VERSION 5.7 ;
  NOWIREEXTENSIONATPIN ON ;
  DIVIDERCHAR "/" ;
  BUSBITCHARS "[]" ;
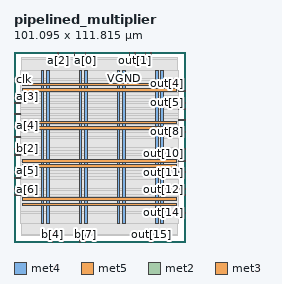
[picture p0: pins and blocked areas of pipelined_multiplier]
MACRO pipelined_multiplier
  CLASS BLOCK ;
  FOREIGN pipelined_multiplier ;
  ORIGIN 0.000 0.000 ;
  SIZE 101.095 BY 111.815 ;
  PIN VGND
    DIRECTION INOUT ;
    USE GROUND ;
    PORT
      LAYER met4 ;
        RECT 19.230 10.640 20.830 100.880 ;
    END
    PORT
      LAYER met4 ;
        RECT 41.655 10.640 43.255 100.880 ;
    END
    PORT
      LAYER met4 ;
        RECT 64.080 10.640 65.680 100.880 ;
    END
    PORT
      LAYER met4 ;
        RECT 86.505 10.640 88.105 100.880 ;
    END
    PORT
      LAYER met5 ;
        RECT 5.280 24.600 95.460 26.200 ;
    END
    PORT
      LAYER met5 ;
        RECT 5.280 47.040 95.460 48.640 ;
    END
    PORT
      LAYER met5 ;
        RECT 5.280 69.480 95.460 71.080 ;
    END
    PORT
      LAYER met5 ;
        RECT 5.280 91.920 95.460 93.520 ;
    END
  END VGND
  PIN VPWR
    DIRECTION INOUT ;
    USE POWER ;
    PORT
      LAYER met4 ;
        RECT 15.930 10.640 17.530 100.880 ;
    END
    PORT
      LAYER met4 ;
        RECT 38.355 10.640 39.955 100.880 ;
    END
    PORT
      LAYER met4 ;
        RECT 60.780 10.640 62.380 100.880 ;
    END
    PORT
      LAYER met4 ;
        RECT 83.205 10.640 84.805 100.880 ;
    END
    PORT
      LAYER met5 ;
        RECT 5.280 21.300 95.460 22.900 ;
    END
    PORT
      LAYER met5 ;
        RECT 5.280 43.740 95.460 45.340 ;
    END
    PORT
      LAYER met5 ;
        RECT 5.280 66.180 95.460 67.780 ;
    END
    PORT
      LAYER met5 ;
        RECT 5.280 88.620 95.460 90.220 ;
    END
  END VPWR
  PIN a[0]
    DIRECTION INPUT ;
    USE SIGNAL ;
    ANTENNAGATEAREA 0.196500 ;
    PORT
      LAYER met2 ;
        RECT 41.950 107.815 42.230 111.815 ;
    END
  END a[0]
  PIN a[1]
    DIRECTION INPUT ;
    USE SIGNAL ;
    ANTENNAGATEAREA 0.196500 ;
    PORT
      LAYER met2 ;
        RECT 35.510 107.815 35.790 111.815 ;
    END
  END a[1]
  PIN a[2]
    DIRECTION INPUT ;
    USE SIGNAL ;
    ANTENNAGATEAREA 0.196500 ;
    PORT
      LAYER met2 ;
        RECT 25.850 107.815 26.130 111.815 ;
    END
  END a[2]
  PIN a[3]
    DIRECTION INPUT ;
    USE SIGNAL ;
    ANTENNAGATEAREA 0.196500 ;
    PORT
      LAYER met3 ;
        RECT 0.000 85.040 4.000 85.640 ;
    END
  END a[3]
  PIN a[4]
    DIRECTION INPUT ;
    USE SIGNAL ;
    ANTENNAGATEAREA 0.196500 ;
    PORT
      LAYER met3 ;
        RECT 0.000 68.040 4.000 68.640 ;
    END
  END a[4]
  PIN a[5]
    DIRECTION INPUT ;
    USE SIGNAL ;
    ANTENNAGATEAREA 0.196500 ;
    PORT
      LAYER met3 ;
        RECT 0.000 37.440 4.000 38.040 ;
    END
  END a[5]
  PIN a[6]
    DIRECTION INPUT ;
    USE SIGNAL ;
    ANTENNAGATEAREA 0.196500 ;
    PORT
      LAYER met3 ;
        RECT 0.000 30.640 4.000 31.240 ;
    END
  END a[6]
  PIN a[7]
    DIRECTION INPUT ;
    USE SIGNAL ;
    ANTENNAGATEAREA 0.196500 ;
    PORT
      LAYER met3 ;
        RECT 0.000 27.240 4.000 27.840 ;
    END
  END a[7]
  PIN b[0]
    DIRECTION INPUT ;
    USE SIGNAL ;
    ANTENNAGATEAREA 0.196500 ;
    PORT
      LAYER met3 ;
        RECT 0.000 81.640 4.000 82.240 ;
    END
  END b[0]
  PIN b[1]
    DIRECTION INPUT ;
    USE SIGNAL ;
    ANTENNAGATEAREA 0.196500 ;
    PORT
      LAYER met3 ;
        RECT 0.000 74.840 4.000 75.440 ;
    END
  END b[1]
  PIN b[2]
    DIRECTION INPUT ;
    USE SIGNAL ;
    ANTENNAGATEAREA 0.196500 ;
    PORT
      LAYER met3 ;
        RECT 0.000 54.440 4.000 55.040 ;
    END
  END b[2]
  PIN b[3]
    DIRECTION INPUT ;
    USE SIGNAL ;
    ANTENNAGATEAREA 0.196500 ;
    PORT
      LAYER met3 ;
        RECT 0.000 61.240 4.000 61.840 ;
    END
  END b[3]
  PIN b[4]
    DIRECTION INPUT ;
    USE SIGNAL ;
    ANTENNAGATEAREA 0.196500 ;
    PORT
      LAYER met2 ;
        RECT 22.630 0.000 22.910 4.000 ;
    END
  END b[4]
  PIN b[5]
    DIRECTION INPUT ;
    USE SIGNAL ;
    ANTENNAGATEAREA 0.196500 ;
    PORT
      LAYER met2 ;
        RECT 29.070 0.000 29.350 4.000 ;
    END
  END b[5]
  PIN b[6]
    DIRECTION INPUT ;
    USE SIGNAL ;
    ANTENNAGATEAREA 0.196500 ;
    PORT
      LAYER met2 ;
        RECT 38.730 0.000 39.010 4.000 ;
    END
  END b[6]
  PIN b[7]
    DIRECTION INPUT ;
    USE SIGNAL ;
    ANTENNAGATEAREA 0.196500 ;
    PORT
      LAYER met2 ;
        RECT 41.950 0.000 42.230 4.000 ;
    END
  END b[7]
  PIN clk
    DIRECTION INPUT ;
    USE SIGNAL ;
    ANTENNAGATEAREA 0.742500 ;
    PORT
      LAYER met3 ;
        RECT 0.000 95.240 4.000 95.840 ;
    END
  END clk
  PIN out[0]
    DIRECTION OUTPUT TRISTATE ;
    USE SIGNAL ;
    ANTENNADIFFAREA 0.340600 ;
    PORT
      LAYER met2 ;
        RECT 67.710 107.815 67.990 111.815 ;
    END
  END out[0]
  PIN out[10]
    DIRECTION OUTPUT TRISTATE ;
    USE SIGNAL ;
    ANTENNADIFFAREA 0.340600 ;
    PORT
      LAYER met3 ;
        RECT 97.095 47.640 101.095 48.240 ;
    END
  END out[10]
  PIN out[11]
    DIRECTION OUTPUT TRISTATE ;
    USE SIGNAL ;
    ANTENNADIFFAREA 0.340600 ;
    PORT
      LAYER met3 ;
        RECT 97.095 40.840 101.095 41.440 ;
    END
  END out[11]
  PIN out[12]
    DIRECTION OUTPUT TRISTATE ;
    USE SIGNAL ;
    ANTENNADIFFAREA 0.340600 ;
    PORT
      LAYER met3 ;
        RECT 97.095 30.640 101.095 31.240 ;
    END
  END out[12]
  PIN out[13]
    DIRECTION OUTPUT TRISTATE ;
    USE SIGNAL ;
    ANTENNADIFFAREA 0.340600 ;
    PORT
      LAYER met3 ;
        RECT 97.095 27.240 101.095 27.840 ;
    END
  END out[13]
  PIN out[14]
    DIRECTION OUTPUT TRISTATE ;
    USE SIGNAL ;
    ANTENNADIFFAREA 0.340600 ;
    PORT
      LAYER met3 ;
        RECT 97.095 17.040 101.095 17.640 ;
    END
  END out[14]
  PIN out[15]
    DIRECTION OUTPUT TRISTATE ;
    USE SIGNAL ;
    ANTENNADIFFAREA 0.340600 ;
    PORT
      LAYER met2 ;
        RECT 80.590 0.000 80.870 4.000 ;
    END
  END out[15]
  PIN out[1]
    DIRECTION OUTPUT TRISTATE ;
    USE SIGNAL ;
    ANTENNADIFFAREA 0.340600 ;
    PORT
      LAYER met2 ;
        RECT 70.930 107.815 71.210 111.815 ;
    END
  END out[1]
  PIN out[2]
    DIRECTION OUTPUT TRISTATE ;
    USE SIGNAL ;
    ANTENNADIFFAREA 0.340600 ;
    PORT
      LAYER met2 ;
        RECT 77.370 107.815 77.650 111.815 ;
    END
  END out[2]
  PIN out[3]
    DIRECTION OUTPUT TRISTATE ;
    USE SIGNAL ;
    ANTENNADIFFAREA 0.340600 ;
    PORT
      LAYER met2 ;
        RECT 80.590 107.815 80.870 111.815 ;
    END
  END out[3]
  PIN out[4]
    DIRECTION OUTPUT TRISTATE ;
    USE SIGNAL ;
    ANTENNADIFFAREA 0.340600 ;
    PORT
      LAYER met3 ;
        RECT 97.095 88.440 101.095 89.040 ;
    END
  END out[4]
  PIN out[5]
    DIRECTION OUTPUT TRISTATE ;
    USE SIGNAL ;
    ANTENNADIFFAREA 0.340600 ;
    PORT
      LAYER met3 ;
        RECT 97.095 81.640 101.095 82.240 ;
    END
  END out[5]
  PIN out[6]
    DIRECTION OUTPUT TRISTATE ;
    USE SIGNAL ;
    ANTENNADIFFAREA 0.340600 ;
    PORT
      LAYER met3 ;
        RECT 97.095 78.240 101.095 78.840 ;
    END
  END out[6]
  PIN out[7]
    DIRECTION OUTPUT TRISTATE ;
    USE SIGNAL ;
    ANTENNADIFFAREA 0.340600 ;
    PORT
      LAYER met3 ;
        RECT 97.095 71.440 101.095 72.040 ;
    END
  END out[7]
  PIN out[8]
    DIRECTION OUTPUT TRISTATE ;
    USE SIGNAL ;
    ANTENNADIFFAREA 0.340600 ;
    PORT
      LAYER met3 ;
        RECT 97.095 64.640 101.095 65.240 ;
    END
  END out[8]
  PIN out[9]
    DIRECTION OUTPUT TRISTATE ;
    USE SIGNAL ;
    ANTENNADIFFAREA 0.340600 ;
    PORT
      LAYER met3 ;
        RECT 97.095 54.440 101.095 55.040 ;
    END
  END out[9]
  PIN reset
    DIRECTION INPUT ;
    USE SIGNAL ;
    ANTENNAGATEAREA 0.213000 ;
    PORT
      LAYER met3 ;
        RECT 0.000 51.040 4.000 51.640 ;
    END
  END reset
  OBS
      LAYER li1 ;
        RECT 5.520 10.795 95.220 100.725 ;
      LAYER met1 ;
        RECT 4.210 10.640 96.070 100.880 ;
      LAYER met2 ;
        RECT 4.230 107.535 25.570 108.530 ;
        RECT 26.410 107.535 35.230 108.530 ;
        RECT 36.070 107.535 41.670 108.530 ;
        RECT 42.510 107.535 67.430 108.530 ;
        RECT 68.270 107.535 70.650 108.530 ;
        RECT 71.490 107.535 77.090 108.530 ;
        RECT 77.930 107.535 80.310 108.530 ;
        RECT 81.150 107.535 96.050 108.530 ;
        RECT 4.230 4.280 96.050 107.535 ;
        RECT 4.230 3.670 22.350 4.280 ;
        RECT 23.190 3.670 28.790 4.280 ;
        RECT 29.630 3.670 38.450 4.280 ;
        RECT 39.290 3.670 41.670 4.280 ;
        RECT 42.510 3.670 80.310 4.280 ;
        RECT 81.150 3.670 96.050 4.280 ;
      LAYER met3 ;
        RECT 3.750 96.240 97.095 100.805 ;
        RECT 4.400 94.840 97.095 96.240 ;
        RECT 3.750 89.440 97.095 94.840 ;
        RECT 3.750 88.040 96.695 89.440 ;
        RECT 3.750 86.040 97.095 88.040 ;
        RECT 4.400 84.640 97.095 86.040 ;
        RECT 3.750 82.640 97.095 84.640 ;
        RECT 4.400 81.240 96.695 82.640 ;
        RECT 3.750 79.240 97.095 81.240 ;
        RECT 3.750 77.840 96.695 79.240 ;
        RECT 3.750 75.840 97.095 77.840 ;
        RECT 4.400 74.440 97.095 75.840 ;
        RECT 3.750 72.440 97.095 74.440 ;
        RECT 3.750 71.040 96.695 72.440 ;
        RECT 3.750 69.040 97.095 71.040 ;
        RECT 4.400 67.640 97.095 69.040 ;
        RECT 3.750 65.640 97.095 67.640 ;
        RECT 3.750 64.240 96.695 65.640 ;
        RECT 3.750 62.240 97.095 64.240 ;
        RECT 4.400 60.840 97.095 62.240 ;
        RECT 3.750 55.440 97.095 60.840 ;
        RECT 4.400 54.040 96.695 55.440 ;
        RECT 3.750 52.040 97.095 54.040 ;
        RECT 4.400 50.640 97.095 52.040 ;
        RECT 3.750 48.640 97.095 50.640 ;
        RECT 3.750 47.240 96.695 48.640 ;
        RECT 3.750 41.840 97.095 47.240 ;
        RECT 3.750 40.440 96.695 41.840 ;
        RECT 3.750 38.440 97.095 40.440 ;
        RECT 4.400 37.040 97.095 38.440 ;
        RECT 3.750 31.640 97.095 37.040 ;
        RECT 4.400 30.240 96.695 31.640 ;
        RECT 3.750 28.240 97.095 30.240 ;
        RECT 4.400 26.840 96.695 28.240 ;
        RECT 3.750 18.040 97.095 26.840 ;
        RECT 3.750 16.640 96.695 18.040 ;
        RECT 3.750 10.715 97.095 16.640 ;
      LAYER met4 ;
        RECT 3.975 51.175 4.305 53.545 ;
  END
END pipelined_multiplier
END LIBRARY

